VERSION 5.7 ;
BUSBITCHARS "[]" ;
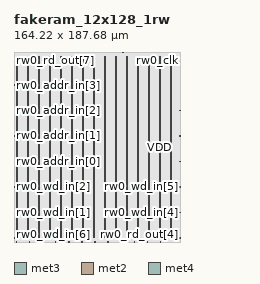
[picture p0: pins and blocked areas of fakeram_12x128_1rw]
MACRO fakeram_12x128_1rw
  FOREIGN fakeram_12x128_1rw 0 0 ;
  SYMMETRY X Y R90 ;
  SIZE 164.220 BY 187.680 ;
  CLASS BLOCK ;
  PIN rw0_wd_in[0]
    DIRECTION INPUT ;
    USE SIGNAL ;
    SHAPE ABUTMENT ;
    PORT
      LAYER met3 ;
      RECT 0.000 3.930 0.900 4.230 ;
    END
  END rw0_wd_in[0]
  PIN rw0_wd_in[1]
    DIRECTION INPUT ;
    USE SIGNAL ;
    SHAPE ABUTMENT ;
    PORT
      LAYER met3 ;
      RECT 0.000 29.090 0.900 29.390 ;
    END
  END rw0_wd_in[1]
  PIN rw0_wd_in[2]
    DIRECTION INPUT ;
    USE SIGNAL ;
    SHAPE ABUTMENT ;
    PORT
      LAYER met3 ;
      RECT 0.000 54.250 0.900 54.550 ;
    END
  END rw0_wd_in[2]
  PIN rw0_wd_in[3]
    DIRECTION INPUT ;
    USE SIGNAL ;
    SHAPE ABUTMENT ;
    PORT
      LAYER met3 ;
      RECT 163.320 3.930 164.220 4.230 ;
    END
  END rw0_wd_in[3]
  PIN rw0_wd_in[4]
    DIRECTION INPUT ;
    USE SIGNAL ;
    SHAPE ABUTMENT ;
    PORT
      LAYER met3 ;
      RECT 163.320 29.090 164.220 29.390 ;
    END
  END rw0_wd_in[4]
  PIN rw0_wd_in[5]
    DIRECTION INPUT ;
    USE SIGNAL ;
    SHAPE ABUTMENT ;
    PORT
      LAYER met3 ;
      RECT 163.320 54.250 164.220 54.550 ;
    END
  END rw0_wd_in[5]
  PIN rw0_wd_in[6]
    DIRECTION OUTPUT ;
    USE SIGNAL ;
    SHAPE ABUTMENT ;
    PORT
      LAYER met2 ;
      RECT 2.690 0.000 2.830 0.420 ;
    END
  END rw0_wd_in[6]
  PIN rw0_wd_in[7]
    DIRECTION OUTPUT ;
    USE SIGNAL ;
    SHAPE ABUTMENT ;
    PORT
      LAYER met2 ;
      RECT 15.570 0.000 15.710 0.420 ;
    END
  END rw0_wd_in[7]
  PIN rw0_wd_in[8]
    DIRECTION OUTPUT ;
    USE SIGNAL ;
    SHAPE ABUTMENT ;
    PORT
      LAYER met2 ;
      RECT 28.450 0.000 28.590 0.420 ;
    END
  END rw0_wd_in[8]
  PIN rw0_wd_in[9]
    DIRECTION OUTPUT ;
    USE SIGNAL ;
    SHAPE ABUTMENT ;
    PORT
      LAYER met2 ;
      RECT 41.330 0.000 41.470 0.420 ;
    END
  END rw0_wd_in[9]
  PIN rw0_wd_in[10]
    DIRECTION OUTPUT ;
    USE SIGNAL ;
    SHAPE ABUTMENT ;
    PORT
      LAYER met2 ;
      RECT 54.210 0.000 54.350 0.420 ;
    END
  END rw0_wd_in[10]
  PIN rw0_wd_in[11]
    DIRECTION OUTPUT ;
    USE SIGNAL ;
    SHAPE ABUTMENT ;
    PORT
      LAYER met2 ;
      RECT 67.090 0.000 67.230 0.420 ;
    END
  END rw0_wd_in[11]
  PIN rw0_rd_out[0]
    DIRECTION OUTPUT ;
    USE SIGNAL ;
    SHAPE ABUTMENT ;
    PORT
      LAYER met2 ;
      RECT 79.970 0.000 80.110 0.420 ;
    END
  END rw0_rd_out[0]
  PIN rw0_rd_out[1]
    DIRECTION OUTPUT ;
    USE SIGNAL ;
    SHAPE ABUTMENT ;
    PORT
      LAYER met2 ;
      RECT 92.850 0.000 92.990 0.420 ;
    END
  END rw0_rd_out[1]
  PIN rw0_rd_out[2]
    DIRECTION OUTPUT ;
    USE SIGNAL ;
    SHAPE ABUTMENT ;
    PORT
      LAYER met2 ;
      RECT 105.730 0.000 105.870 0.420 ;
    END
  END rw0_rd_out[2]
  PIN rw0_rd_out[3]
    DIRECTION OUTPUT ;
    USE SIGNAL ;
    SHAPE ABUTMENT ;
    PORT
      LAYER met2 ;
      RECT 118.610 0.000 118.750 0.420 ;
    END
  END rw0_rd_out[3]
  PIN rw0_rd_out[4]
    DIRECTION OUTPUT ;
    USE SIGNAL ;
    SHAPE ABUTMENT ;
    PORT
      LAYER met2 ;
      RECT 131.490 0.000 131.630 0.420 ;
    END
  END rw0_rd_out[4]
  PIN rw0_rd_out[5]
    DIRECTION OUTPUT ;
    USE SIGNAL ;
    SHAPE ABUTMENT ;
    PORT
      LAYER met2 ;
      RECT 144.370 0.000 144.510 0.420 ;
    END
  END rw0_rd_out[5]
  PIN rw0_rd_out[6]
    DIRECTION OUTPUT ;
    USE SIGNAL ;
    SHAPE ABUTMENT ;
    PORT
      LAYER met2 ;
      RECT 2.690 187.260 2.830 187.680 ;
    END
  END rw0_rd_out[6]
  PIN rw0_rd_out[7]
    DIRECTION OUTPUT ;
    USE SIGNAL ;
    SHAPE ABUTMENT ;
    PORT
      LAYER met2 ;
      RECT 20.170 187.260 20.310 187.680 ;
    END
  END rw0_rd_out[7]
  PIN rw0_rd_out[8]
    DIRECTION OUTPUT ;
    USE SIGNAL ;
    SHAPE ABUTMENT ;
    PORT
      LAYER met2 ;
      RECT 37.650 187.260 37.790 187.680 ;
    END
  END rw0_rd_out[8]
  PIN rw0_rd_out[9]
    DIRECTION OUTPUT ;
    USE SIGNAL ;
    SHAPE ABUTMENT ;
    PORT
      LAYER met2 ;
      RECT 55.130 187.260 55.270 187.680 ;
    END
  END rw0_rd_out[9]
  PIN rw0_rd_out[10]
    DIRECTION OUTPUT ;
    USE SIGNAL ;
    SHAPE ABUTMENT ;
    PORT
      LAYER met2 ;
      RECT 72.610 187.260 72.750 187.680 ;
    END
  END rw0_rd_out[10]
  PIN rw0_rd_out[11]
    DIRECTION OUTPUT ;
    USE SIGNAL ;
    SHAPE ABUTMENT ;
    PORT
      LAYER met2 ;
      RECT 90.090 187.260 90.230 187.680 ;
    END
  END rw0_rd_out[11]
  PIN rw0_addr_in[0]
    DIRECTION INPUT ;
    USE SIGNAL ;
    SHAPE ABUTMENT ;
    PORT
      LAYER met3 ;
      RECT 0.000 79.410 0.900 79.710 ;
    END
  END rw0_addr_in[0]
  PIN rw0_addr_in[1]
    DIRECTION INPUT ;
    USE SIGNAL ;
    SHAPE ABUTMENT ;
    PORT
      LAYER met3 ;
      RECT 0.000 104.570 0.900 104.870 ;
    END
  END rw0_addr_in[1]
  PIN rw0_addr_in[2]
    DIRECTION INPUT ;
    USE SIGNAL ;
    SHAPE ABUTMENT ;
    PORT
      LAYER met3 ;
      RECT 0.000 129.730 0.900 130.030 ;
    END
  END rw0_addr_in[2]
  PIN rw0_addr_in[3]
    DIRECTION INPUT ;
    USE SIGNAL ;
    SHAPE ABUTMENT ;
    PORT
      LAYER met3 ;
      RECT 0.000 154.890 0.900 155.190 ;
    END
  END rw0_addr_in[3]
  PIN rw0_addr_in[4]
    DIRECTION INPUT ;
    USE SIGNAL ;
    SHAPE ABUTMENT ;
    PORT
      LAYER met3 ;
      RECT 163.320 79.410 164.220 79.710 ;
    END
  END rw0_addr_in[4]
  PIN rw0_addr_in[5]
    DIRECTION INPUT ;
    USE SIGNAL ;
    SHAPE ABUTMENT ;
    PORT
      LAYER met3 ;
      RECT 163.320 104.570 164.220 104.870 ;
    END
  END rw0_addr_in[5]
  PIN rw0_addr_in[6]
    DIRECTION INPUT ;
    USE SIGNAL ;
    SHAPE ABUTMENT ;
    PORT
      LAYER met3 ;
      RECT 163.320 129.730 164.220 130.030 ;
    END
  END rw0_addr_in[6]
  PIN rw0_we_in
    DIRECTION INPUT ;
    USE SIGNAL ;
    SHAPE ABUTMENT ;
    PORT
      LAYER met2 ;
      RECT 107.570 187.260 107.710 187.680 ;
    END
  END rw0_we_in
  PIN rw0_ce_in
    DIRECTION INPUT ;
    USE SIGNAL ;
    SHAPE ABUTMENT ;
    PORT
      LAYER met2 ;
      RECT 125.050 187.260 125.190 187.680 ;
    END
  END rw0_ce_in
  PIN rw0_clk
    DIRECTION INPUT ;
    USE SIGNAL ;
    SHAPE ABUTMENT ;
    PORT
      LAYER met2 ;
      RECT 142.530 187.260 142.670 187.680 ;
    END
  END rw0_clk
  PIN VSS
    DIRECTION INOUT ;
    USE GROUND ;
    PORT
      LAYER met4 ;
      RECT 2.160 4.080 3.360 183.600 ;
      RECT 13.040 4.080 14.240 183.600 ;
      RECT 23.920 4.080 25.120 183.600 ;
      RECT 34.800 4.080 36.000 183.600 ;
      RECT 45.680 4.080 46.880 183.600 ;
      RECT 56.560 4.080 57.760 183.600 ;
      RECT 67.440 4.080 68.640 183.600 ;
      RECT 78.320 4.080 79.520 183.600 ;
      RECT 89.200 4.080 90.400 183.600 ;
      RECT 100.080 4.080 101.280 183.600 ;
      RECT 110.960 4.080 112.160 183.600 ;
      RECT 121.840 4.080 123.040 183.600 ;
      RECT 132.720 4.080 133.920 183.600 ;
      RECT 143.600 4.080 144.800 183.600 ;
      RECT 154.480 4.080 155.680 183.600 ;
    END
  END VSS
  PIN VDD
    DIRECTION INOUT ;
    USE POWER ;
    PORT
      LAYER met4 ;
      RECT 2.160 4.080 3.360 183.600 ;
      RECT 13.040 4.080 14.240 183.600 ;
      RECT 23.920 4.080 25.120 183.600 ;
      RECT 34.800 4.080 36.000 183.600 ;
      RECT 45.680 4.080 46.880 183.600 ;
      RECT 56.560 4.080 57.760 183.600 ;
      RECT 67.440 4.080 68.640 183.600 ;
      RECT 78.320 4.080 79.520 183.600 ;
      RECT 89.200 4.080 90.400 183.600 ;
      RECT 100.080 4.080 101.280 183.600 ;
      RECT 110.960 4.080 112.160 183.600 ;
      RECT 121.840 4.080 123.040 183.600 ;
      RECT 132.720 4.080 133.920 183.600 ;
      RECT 143.600 4.080 144.800 183.600 ;
      RECT 154.480 4.080 155.680 183.600 ;
    END
  END VDD
  OBS
    LAYER met1 ;
    RECT 0 0 164.220 187.680 ;
    LAYER met2 ;
    RECT 0 0 164.220 187.680 ;
    LAYER met3 ;
    RECT 0 0 164.220 187.680 ;
    LAYER met4 ;
    RECT 0 0 164.220 187.680 ;
  END
END fakeram_12x128_1rw

END LIBRARY
